VERSION 5.8 ;
BUSBITCHARS "[]" ;
DIVIDERCHAR "/" ;

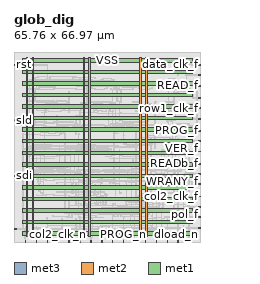
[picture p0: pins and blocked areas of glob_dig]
MACRO glob_dig
  CLASS BLOCK ;
  FOREIGN glob_dig 0 0 ;
  ORIGIN 0 0 ;
  SIZE 65.760 BY 66.970 ;
  SYMMETRY X Y ;
  PIN PROG_f
    DIRECTION OUTPUT ;
    USE SIGNAL ;
    PORT
      LAYER met3 ;
        RECT 64.960 39.075 65.760 39.375 ;
    END
  END PROG_f
  PIN PROG_n
    DIRECTION OUTPUT ;
    USE SIGNAL ;
    PORT
      LAYER met2 ;
        RECT 38.570 0.000 38.710 0.485 ;
    END
  END PROG_n
  PIN READ_f
    DIRECTION OUTPUT ;
    USE SIGNAL ;
    PORT
      LAYER met3 ;
        RECT 64.960 54.935 65.760 55.235 ;
    END
  END READ_f
  PIN READ_n
    DIRECTION OUTPUT ;
    USE SIGNAL ;
    PORT
      LAYER met2 ;
        RECT 53.930 0.000 54.070 0.485 ;
    END
  END READ_n
  PIN READb_f
    DIRECTION OUTPUT ;
    USE SIGNAL ;
    PORT
      LAYER met3 ;
        RECT 64.960 27.485 65.760 27.785 ;
    END
  END READb_f
  PIN READb_n
    DIRECTION OUTPUT ;
    USE SIGNAL ;
    PORT
      LAYER met2 ;
        RECT 27.050 0.000 27.190 0.485 ;
    END
  END READb_n
  PIN SENSE_f
    DIRECTION OUTPUT ;
    USE SIGNAL ;
    PORT
      LAYER met3 ;
        RECT 64.960 31.755 65.760 32.055 ;
    END
  END SENSE_f
  PIN SENSE_n
    DIRECTION OUTPUT ;
    USE SIGNAL ;
    PORT
      LAYER met2 ;
        RECT 30.890 0.000 31.030 0.485 ;
    END
  END SENSE_n
  PIN VDD
    DIRECTION INOUT ;
    USE POWER ;
    PORT
      LAYER met1 ;
        RECT 2.880 2.335 62.880 3.585 ;
        RECT 2.880 10.475 62.880 11.725 ;
        RECT 2.880 18.615 62.880 19.865 ;
        RECT 2.880 26.755 62.880 28.005 ;
        RECT 2.880 34.895 62.880 36.145 ;
        RECT 2.880 43.035 62.880 44.285 ;
        RECT 2.880 51.175 62.880 52.425 ;
        RECT 2.880 59.315 62.880 60.565 ;
      LAYER met2 ;
        RECT 4.380 2.060 4.880 64.910 ;
        RECT 24.380 2.060 24.880 64.910 ;
        RECT 44.380 2.060 44.880 64.910 ;
    END
  END VDD
  PIN VER_f
    DIRECTION OUTPUT ;
    USE SIGNAL ;
    PORT
      LAYER met3 ;
        RECT 64.960 35.415 65.760 35.715 ;
    END
  END VER_f
  PIN VER_n
    DIRECTION OUTPUT ;
    USE SIGNAL ;
    PORT
      LAYER met2 ;
        RECT 34.730 0.000 34.870 0.485 ;
    END
  END VER_n
  PIN VSS
    DIRECTION INOUT ;
    USE GROUND ;
    PORT
      LAYER met1 ;
        RECT 2.880 6.405 62.880 7.655 ;
        RECT 2.880 14.545 62.880 15.795 ;
        RECT 2.880 22.685 62.880 23.935 ;
        RECT 2.880 30.825 62.880 32.075 ;
        RECT 2.880 38.965 62.880 40.215 ;
        RECT 2.880 47.105 62.880 48.355 ;
        RECT 2.880 55.245 62.880 56.495 ;
        RECT 2.880 63.385 62.880 64.635 ;
      LAYER met2 ;
        RECT 6.380 2.060 6.880 64.910 ;
        RECT 26.380 2.060 26.880 64.910 ;
        RECT 46.380 2.060 46.880 64.910 ;
    END
  END VSS
  PIN WRANY_f
    DIRECTION OUTPUT ;
    USE SIGNAL ;
    PORT
      LAYER met3 ;
        RECT 64.960 23.825 65.760 24.125 ;
    END
  END WRANY_f
  PIN WRANY_n
    DIRECTION OUTPUT ;
    USE SIGNAL ;
    PORT
      LAYER met2 ;
        RECT 23.210 0.000 23.350 0.485 ;
    END
  END WRANY_n
  PIN col1_clk_f
    DIRECTION OUTPUT ;
    USE SIGNAL ;
    PORT
      LAYER met3 ;
        RECT 64.960 20.165 65.760 20.465 ;
    END
  END col1_clk_f
  PIN col1_clk_n
    DIRECTION OUTPUT ;
    USE SIGNAL ;
    PORT
      LAYER met2 ;
        RECT 19.370 0.000 19.510 0.485 ;
    END
  END col1_clk_n
  PIN col2_clk_f
    DIRECTION OUTPUT ;
    USE SIGNAL ;
    PORT
      LAYER met3 ;
        RECT 64.960 15.895 65.760 16.195 ;
    END
  END col2_clk_f
  PIN col2_clk_n
    DIRECTION OUTPUT ;
    USE SIGNAL ;
    PORT
      LAYER met2 ;
        RECT 15.530 0.000 15.670 0.485 ;
    END
  END col2_clk_n
  PIN data_clk_f
    DIRECTION OUTPUT ;
    USE SIGNAL ;
    PORT
      LAYER met3 ;
        RECT 64.960 62.255 65.760 62.555 ;
    END
  END data_clk_f
  PIN data_clk_n
    DIRECTION OUTPUT ;
    USE SIGNAL ;
    PORT
      LAYER met2 ;
        RECT 61.610 0.000 61.750 0.485 ;
    END
  END data_clk_n
  PIN dload_f
    DIRECTION OUTPUT ;
    USE SIGNAL ;
    PORT
      LAYER met3 ;
        RECT 64.960 58.595 65.760 58.895 ;
    END
  END dload_f
  PIN dload_n
    DIRECTION OUTPUT ;
    USE SIGNAL ;
    PORT
      LAYER met2 ;
        RECT 57.770 0.000 57.910 0.485 ;
    END
  END dload_n
  PIN pol_f
    DIRECTION OUTPUT ;
    USE SIGNAL ;
    PORT
      LAYER met3 ;
        RECT 64.960 12.235 65.760 12.535 ;
    END
  END pol_f
  PIN pol_n
    DIRECTION OUTPUT ;
    USE SIGNAL ;
    PORT
      LAYER met2 ;
        RECT 11.690 0.000 11.830 0.485 ;
    END
  END pol_n
  PIN rd_out_b_f
    DIRECTION OUTPUT ;
    USE SIGNAL ;
    PORT
      LAYER met3 ;
        RECT 64.960 4.915 65.760 5.215 ;
    END
  END rd_out_b_f
  PIN rd_out_b_n
    DIRECTION OUTPUT ;
    USE SIGNAL ;
    PORT
      LAYER met2 ;
        RECT 4.010 0.000 4.150 0.485 ;
    END
  END rd_out_b_n
  PIN rd_out_f
    DIRECTION OUTPUT ;
    USE SIGNAL ;
    PORT
      LAYER met3 ;
        RECT 64.960 8.575 65.760 8.875 ;
    END
  END rd_out_f
  PIN rd_out_n
    DIRECTION OUTPUT ;
    USE SIGNAL ;
    PORT
      LAYER met2 ;
        RECT 7.850 0.000 7.990 0.485 ;
    END
  END rd_out_n
  PIN row1_clk_f
    DIRECTION OUTPUT ;
    USE SIGNAL ;
    PORT
      LAYER met3 ;
        RECT 64.960 47.005 65.760 47.305 ;
    END
  END row1_clk_f
  PIN row1_clk_n
    DIRECTION OUTPUT ;
    USE SIGNAL ;
    PORT
      LAYER met2 ;
        RECT 46.250 0.000 46.390 0.485 ;
    END
  END row1_clk_n
  PIN row2_clk_f
    DIRECTION OUTPUT ;
    USE SIGNAL ;
    PORT
      LAYER met3 ;
        RECT 64.960 43.345 65.760 43.645 ;
    END
  END row2_clk_f
  PIN row2_clk_n
    DIRECTION OUTPUT ;
    USE SIGNAL ;
    PORT
      LAYER met2 ;
        RECT 42.410 0.000 42.550 0.485 ;
    END
  END row2_clk_n
  PIN rst
    DIRECTION INPUT ;
    USE SIGNAL ;
    PORT
      LAYER met3 ;
        RECT 0.000 62.255 0.800 62.555 ;
    END
  END rst
  PIN rstb_f
    DIRECTION OUTPUT ;
    USE SIGNAL ;
    PORT
      LAYER met3 ;
        RECT 64.960 50.665 65.760 50.965 ;
    END
  END rstb_f
  PIN rstb_n
    DIRECTION OUTPUT ;
    USE SIGNAL ;
    PORT
      LAYER met2 ;
        RECT 50.090 0.000 50.230 0.485 ;
    END
  END rstb_n
  PIN sck
    DIRECTION INPUT ;
    USE SIGNAL ;
    PORT
      LAYER met3 ;
        RECT 0.000 4.305 0.800 4.605 ;
    END
  END sck
  PIN sdi
    DIRECTION INPUT ;
    USE SIGNAL ;
    PORT
      LAYER met3 ;
        RECT 0.000 23.215 0.800 23.515 ;
    END
  END sdi
  PIN sld
    DIRECTION INPUT ;
    USE SIGNAL ;
    PORT
      LAYER met3 ;
        RECT 0.000 42.735 0.800 43.035 ;
    END
  END sld
  OBS
    LAYER li1 ;
      RECT 0.000 0.000 65.760 66.970 ;
    LAYER met1 ;
      RECT 30.335 4.510 30.625 4.555 ;
      RECT 30.335 4.695 30.625 4.740 ;
      RECT 11.210 4.555 36.650 4.695 ;
      RECT 36.650 4.325 36.790 4.695 ;
      RECT 6.815 4.880 7.105 4.925 ;
      RECT 40.970 4.185 41.110 4.555 ;
      RECT 36.650 4.185 40.970 4.325 ;
      RECT 41.930 4.555 42.070 4.925 ;
      RECT 40.970 4.555 41.930 4.695 ;
      RECT 7.105 4.925 11.210 5.065 ;
      RECT 6.815 4.925 7.105 5.110 ;
      RECT 11.210 4.695 11.350 5.065 ;
      RECT 41.930 4.925 61.055 5.065 ;
      RECT 61.055 4.880 61.345 5.110 ;
      RECT 29.375 5.435 29.665 5.480 ;
      RECT 11.690 5.110 11.830 5.665 ;
      RECT 11.615 4.880 11.905 5.110 ;
      RECT 11.690 5.665 22.250 5.805 ;
      RECT 22.250 5.435 22.390 5.805 ;
      RECT 30.410 5.295 30.550 5.805 ;
      RECT 31.370 5.665 31.510 5.850 ;
      RECT 30.550 5.665 31.370 5.805 ;
      RECT 22.250 5.295 30.410 5.435 ;
      RECT 29.375 5.250 29.665 5.295 ;
      RECT 33.770 5.665 48.560 5.805 ;
      RECT 48.560 5.605 48.880 5.865 ;
      RECT 31.370 5.850 33.770 5.990 ;
      RECT 33.770 5.805 33.910 5.990 ;
      RECT 18.335 8.765 18.625 8.810 ;
      RECT 24.170 9.735 24.310 9.920 ;
      RECT 21.290 9.735 24.170 9.875 ;
      RECT 24.170 9.920 29.930 10.060 ;
      RECT 29.930 9.875 30.070 10.060 ;
      RECT 17.840 10.045 18.160 10.105 ;
      RECT 20.330 8.625 20.470 10.105 ;
      RECT 18.335 8.580 18.625 8.765 ;
      RECT 18.625 8.625 20.330 8.765 ;
      RECT 44.330 9.735 44.470 10.105 ;
      RECT 29.930 9.735 44.330 9.875 ;
      RECT 18.160 10.105 21.290 10.245 ;
      RECT 17.840 10.105 18.160 10.305 ;
      RECT 21.290 9.875 21.430 10.245 ;
      RECT 44.330 10.105 45.200 10.245 ;
      RECT 45.200 10.045 45.520 10.305 ;
      RECT 30.815 12.095 31.105 12.140 ;
      RECT 31.850 11.955 31.990 12.140 ;
      RECT 30.815 11.910 31.105 12.095 ;
      RECT 31.105 11.955 31.850 12.095 ;
      RECT 35.690 11.955 37.520 12.095 ;
      RECT 37.520 11.895 37.840 12.155 ;
      RECT 31.850 12.140 35.690 12.280 ;
      RECT 35.690 12.095 35.830 12.280 ;
      RECT 19.280 12.635 19.600 12.835 ;
      RECT 36.170 12.695 36.310 12.880 ;
      RECT 19.600 12.695 36.170 12.835 ;
      RECT 19.280 12.835 19.600 12.895 ;
      RECT 36.170 12.880 38.570 13.020 ;
      RECT 38.570 12.835 38.710 13.020 ;
      RECT 51.530 13.065 61.055 13.205 ;
      RECT 61.055 13.020 61.345 13.250 ;
      RECT 40.010 12.695 40.150 13.205 ;
      RECT 38.570 12.695 40.010 12.835 ;
      RECT 49.130 13.065 49.270 13.435 ;
      RECT 40.150 13.065 49.130 13.205 ;
      RECT 49.130 13.435 51.530 13.575 ;
      RECT 51.530 13.205 51.670 13.575 ;
      RECT 33.695 20.790 33.985 20.835 ;
      RECT 33.985 20.835 34.730 20.975 ;
      RECT 33.695 20.835 33.985 21.020 ;
      RECT 34.730 20.605 34.870 20.975 ;
      RECT 37.130 20.465 37.270 21.205 ;
      RECT 34.730 20.465 37.130 20.605 ;
      RECT 39.440 21.145 39.760 21.205 ;
      RECT 42.890 21.020 43.030 21.205 ;
      RECT 40.490 21.020 42.890 21.160 ;
      RECT 42.890 21.205 49.535 21.345 ;
      RECT 49.535 21.160 49.825 21.390 ;
      RECT 39.440 21.345 39.760 21.405 ;
      RECT 37.130 21.205 40.490 21.345 ;
      RECT 40.490 21.160 40.630 21.345 ;
      RECT 7.775 21.900 8.065 21.945 ;
      RECT 10.160 21.885 10.480 21.945 ;
      RECT 14.090 21.575 14.230 21.945 ;
      RECT 11.210 21.575 14.090 21.715 ;
      RECT 17.855 21.900 18.145 21.945 ;
      RECT 31.850 21.205 31.990 21.945 ;
      RECT 24.650 21.205 31.850 21.345 ;
      RECT 34.655 21.900 34.945 21.945 ;
      RECT 7.775 22.085 8.065 22.130 ;
      RECT 17.855 22.085 18.145 22.130 ;
      RECT 14.090 21.945 24.650 22.085 ;
      RECT 24.650 21.345 24.790 22.085 ;
      RECT 34.655 22.085 34.945 22.130 ;
      RECT 10.160 22.085 10.480 22.145 ;
      RECT 7.775 21.945 11.210 22.085 ;
      RECT 11.210 21.715 11.350 22.085 ;
      RECT 31.850 21.945 35.600 22.085 ;
      RECT 35.600 21.885 35.920 22.145 ;
      RECT 31.775 24.490 32.065 24.535 ;
      RECT 32.065 24.535 38.570 24.675 ;
      RECT 31.775 24.535 32.065 24.720 ;
      RECT 38.570 24.490 38.710 24.675 ;
      RECT 44.735 24.860 45.025 25.090 ;
      RECT 44.810 24.535 44.950 24.860 ;
      RECT 41.930 24.350 42.070 24.675 ;
      RECT 42.070 24.535 44.810 24.675 ;
      RECT 38.570 24.350 41.930 24.490 ;
      RECT 25.040 24.845 25.360 24.905 ;
      RECT 55.295 25.045 55.585 25.090 ;
      RECT 25.360 24.905 26.090 25.045 ;
      RECT 25.040 24.905 25.360 25.105 ;
      RECT 26.090 24.675 26.230 25.045 ;
      RECT 30.410 24.535 30.550 24.905 ;
      RECT 26.090 24.535 30.410 24.675 ;
      RECT 31.370 24.905 31.510 25.275 ;
      RECT 30.410 24.905 31.370 25.045 ;
      RECT 40.490 24.905 40.630 25.275 ;
      RECT 39.050 24.905 40.490 25.045 ;
      RECT 49.610 24.905 49.750 25.275 ;
      RECT 48.650 24.905 49.610 25.045 ;
      RECT 31.370 25.275 39.050 25.415 ;
      RECT 39.050 25.045 39.190 25.415 ;
      RECT 49.610 25.275 53.450 25.415 ;
      RECT 53.450 25.045 53.590 25.415 ;
      RECT 40.895 25.415 41.185 25.460 ;
      RECT 61.130 25.275 62.015 25.415 ;
      RECT 62.015 25.230 62.305 25.460 ;
      RECT 41.930 25.275 42.070 25.645 ;
      RECT 40.895 25.230 41.185 25.275 ;
      RECT 40.490 25.275 41.930 25.415 ;
      RECT 58.730 24.905 58.870 25.645 ;
      RECT 53.450 24.905 58.730 25.045 ;
      RECT 55.295 24.860 55.585 24.905 ;
      RECT 45.290 25.275 48.650 25.415 ;
      RECT 48.650 25.045 48.790 25.415 ;
      RECT 41.930 25.645 45.290 25.785 ;
      RECT 45.290 25.415 45.430 25.785 ;
      RECT 58.730 25.645 61.130 25.785 ;
      RECT 61.130 25.415 61.270 25.785 ;
      RECT 33.695 29.300 33.985 29.345 ;
      RECT 36.095 29.300 36.385 29.345 ;
      RECT 33.695 29.485 33.985 29.530 ;
      RECT 36.095 29.485 36.385 29.530 ;
      RECT 33.695 29.345 41.375 29.485 ;
      RECT 41.375 29.300 41.665 29.530 ;
      RECT 32.255 30.040 32.545 30.085 ;
      RECT 32.255 30.225 32.545 30.270 ;
      RECT 32.255 30.085 34.160 30.225 ;
      RECT 34.160 30.025 34.480 30.285 ;
      RECT 3.455 32.630 3.745 32.675 ;
      RECT 5.360 32.615 5.680 32.675 ;
      RECT 3.455 32.815 3.745 32.860 ;
      RECT 18.815 32.815 19.105 32.860 ;
      RECT 5.360 32.815 5.680 32.875 ;
      RECT 33.290 32.675 34.160 32.815 ;
      RECT 34.160 32.615 34.480 32.875 ;
      RECT 22.730 32.675 22.870 33.000 ;
      RECT 28.970 32.860 29.110 33.045 ;
      RECT 22.870 32.860 28.970 33.000 ;
      RECT 3.455 32.675 22.730 32.815 ;
      RECT 18.815 32.630 19.105 32.675 ;
      RECT 28.970 33.045 33.290 33.185 ;
      RECT 33.290 32.815 33.430 33.185 ;
      RECT 15.920 33.725 16.240 33.785 ;
      RECT 35.120 33.725 35.440 33.785 ;
      RECT 5.855 33.925 6.145 33.970 ;
      RECT 21.215 33.925 21.505 33.970 ;
      RECT 28.490 33.785 36.575 33.925 ;
      RECT 36.575 33.740 36.865 33.970 ;
      RECT 15.920 33.925 16.240 33.985 ;
      RECT 35.120 33.925 35.440 33.985 ;
      RECT 6.890 33.785 7.030 34.155 ;
      RECT 5.855 33.740 6.145 33.925 ;
      RECT 6.145 33.785 6.890 33.925 ;
      RECT 22.250 33.785 22.390 34.155 ;
      RECT 13.130 33.785 22.250 33.925 ;
      RECT 21.215 33.740 21.505 33.785 ;
      RECT 6.890 34.155 13.130 34.295 ;
      RECT 13.130 33.925 13.270 34.295 ;
      RECT 22.250 34.155 28.490 34.295 ;
      RECT 28.490 33.925 28.630 34.295 ;
      RECT 33.695 45.950 33.985 45.995 ;
      RECT 33.695 46.135 33.985 46.180 ;
      RECT 33.695 45.995 34.640 46.135 ;
      RECT 34.640 45.935 34.960 46.195 ;
      RECT 23.120 45.565 23.440 45.625 ;
      RECT 23.120 45.765 23.440 45.825 ;
      RECT 46.175 45.950 46.465 45.995 ;
      RECT 46.250 45.255 46.390 45.950 ;
      RECT 29.450 45.255 46.250 45.395 ;
      RECT 29.375 45.950 29.665 46.180 ;
      RECT 29.450 45.395 29.590 45.950 ;
      RECT 23.120 45.625 29.450 45.765 ;
      RECT 46.175 46.135 46.465 46.180 ;
      RECT 46.175 45.995 47.120 46.135 ;
      RECT 47.120 45.935 47.440 46.195 ;
      RECT 34.655 48.910 34.945 48.955 ;
      RECT 34.655 49.095 34.945 49.140 ;
      RECT 23.600 49.095 23.920 49.155 ;
      RECT 33.770 48.955 35.600 49.095 ;
      RECT 35.600 48.895 35.920 49.155 ;
      RECT 26.570 48.955 26.710 49.325 ;
      RECT 23.600 48.895 23.920 49.095 ;
      RECT 23.920 48.955 26.570 49.095 ;
      RECT 26.570 49.325 33.770 49.465 ;
      RECT 33.770 49.095 33.910 49.465 ;
      RECT 22.160 54.815 22.480 54.875 ;
      RECT 34.250 54.690 34.390 54.875 ;
      RECT 23.210 54.690 34.250 54.830 ;
      RECT 36.080 54.815 36.400 54.875 ;
      RECT 42.890 54.505 43.030 54.875 ;
      RECT 38.090 54.505 42.890 54.645 ;
      RECT 42.890 54.875 47.135 55.015 ;
      RECT 47.135 54.830 47.425 55.060 ;
      RECT 22.480 54.875 23.210 55.015 ;
      RECT 23.210 54.830 23.350 55.015 ;
      RECT 22.160 54.875 22.480 55.075 ;
      RECT 36.080 55.015 36.400 55.075 ;
      RECT 34.250 54.875 38.090 55.015 ;
      RECT 38.090 54.645 38.230 55.015 ;
      RECT 25.520 56.665 25.840 56.725 ;
      RECT 25.520 56.725 33.695 56.865 ;
      RECT 33.695 56.680 33.985 56.910 ;
      RECT 25.520 56.865 25.840 56.925 ;
      RECT 30.335 57.235 30.625 57.280 ;
      RECT 34.250 57.095 35.120 57.235 ;
      RECT 35.120 57.035 35.440 57.295 ;
      RECT 31.370 57.095 31.510 57.465 ;
      RECT 30.335 57.050 30.625 57.235 ;
      RECT 30.625 57.095 31.370 57.235 ;
      RECT 31.370 57.465 34.250 57.605 ;
      RECT 34.250 57.235 34.390 57.605 ;
      RECT 54.320 37.795 54.640 37.855 ;
      RECT 54.320 37.855 56.735 37.995 ;
      RECT 56.735 37.810 57.025 38.040 ;
      RECT 54.320 37.995 54.640 38.055 ;
      RECT 35.600 38.165 35.920 38.225 ;
      RECT 35.600 38.225 36.575 38.365 ;
      RECT 36.575 38.180 36.865 38.410 ;
      RECT 35.600 38.365 35.920 38.425 ;
      RECT 49.055 38.180 49.345 38.225 ;
      RECT 49.055 38.365 49.345 38.410 ;
      RECT 49.055 38.225 53.840 38.365 ;
      RECT 53.840 38.165 54.160 38.425 ;
      RECT 35.120 40.385 35.440 40.645 ;
      RECT 35.615 40.400 35.905 40.445 ;
      RECT 35.615 40.585 35.905 40.630 ;
      RECT 35.615 40.445 38.480 40.585 ;
      RECT 38.480 40.385 38.800 40.645 ;
      RECT 60.095 40.770 60.385 40.815 ;
      RECT 60.095 40.955 60.385 41.000 ;
      RECT 60.095 40.815 64.400 40.955 ;
      RECT 64.400 40.755 64.720 41.015 ;
      RECT 34.640 41.125 34.960 41.185 ;
      RECT 41.930 40.815 42.070 41.185 ;
      RECT 39.530 40.815 41.930 40.955 ;
      RECT 42.800 41.125 43.120 41.185 ;
      RECT 41.930 41.185 52.895 41.325 ;
      RECT 52.895 41.140 53.185 41.370 ;
      RECT 34.960 41.185 35.830 41.325 ;
      RECT 34.640 41.185 34.960 41.385 ;
      RECT 35.830 41.000 39.530 41.140 ;
      RECT 35.690 41.000 35.830 41.185 ;
      RECT 39.530 40.955 39.670 41.140 ;
      RECT 42.800 41.325 43.120 41.385 ;
      RECT 34.175 41.510 34.465 41.555 ;
      RECT 36.575 41.510 36.865 41.555 ;
      RECT 34.175 41.695 34.465 41.740 ;
      RECT 36.575 41.695 36.865 41.740 ;
      RECT 34.175 41.555 41.855 41.695 ;
      RECT 41.855 41.510 42.145 41.740 ;
      RECT 57.200 41.495 57.520 41.555 ;
      RECT 57.200 41.555 61.535 41.695 ;
      RECT 61.535 41.510 61.825 41.740 ;
      RECT 57.200 41.695 57.520 41.755 ;
      RECT 37.040 42.605 37.360 42.665 ;
      RECT 46.250 42.295 46.390 42.665 ;
      RECT 38.090 42.295 46.250 42.435 ;
      RECT 46.250 42.665 47.135 42.805 ;
      RECT 47.135 42.620 47.425 42.850 ;
      RECT 37.360 42.665 38.090 42.805 ;
      RECT 37.040 42.665 37.360 42.865 ;
      RECT 38.090 42.435 38.230 42.805 ;
      RECT 53.855 42.620 54.145 42.665 ;
      RECT 53.855 42.805 54.145 42.850 ;
      RECT 53.855 42.665 55.280 42.805 ;
      RECT 55.280 42.605 55.600 42.865 ;
      RECT 37.040 45.565 37.360 45.625 ;
      RECT 37.040 45.625 37.535 45.765 ;
      RECT 37.535 45.580 37.825 45.810 ;
      RECT 37.040 45.765 37.360 45.825 ;
      RECT 62.015 45.580 62.305 45.625 ;
      RECT 62.015 45.765 62.305 45.810 ;
      RECT 62.015 45.625 62.960 45.765 ;
      RECT 62.960 45.565 63.280 45.825 ;
      RECT 42.815 45.950 43.105 45.995 ;
      RECT 42.815 46.135 43.105 46.180 ;
      RECT 42.815 45.995 44.255 46.135 ;
      RECT 44.255 45.950 44.545 46.180 ;
      RECT 35.615 33.370 35.905 33.415 ;
      RECT 38.015 33.370 38.305 33.415 ;
      RECT 35.615 33.555 35.905 33.600 ;
      RECT 38.015 33.555 38.305 33.600 ;
      RECT 35.615 33.415 43.295 33.555 ;
      RECT 43.295 33.370 43.585 33.600 ;
      RECT 38.480 34.465 38.800 34.525 ;
      RECT 47.690 34.155 47.830 34.525 ;
      RECT 39.530 34.155 47.690 34.295 ;
      RECT 47.690 34.525 48.575 34.665 ;
      RECT 48.575 34.480 48.865 34.710 ;
      RECT 38.800 34.525 39.530 34.665 ;
      RECT 38.480 34.525 38.800 34.725 ;
      RECT 39.530 34.295 39.670 34.665 ;
      RECT 48.080 45.935 48.400 46.195 ;
      RECT 53.375 45.950 53.665 45.995 ;
      RECT 53.375 46.135 53.665 46.180 ;
      RECT 53.375 45.995 54.320 46.135 ;
      RECT 54.320 45.935 54.640 46.195 ;
      RECT 55.280 45.935 55.600 45.995 ;
      RECT 55.280 45.995 55.775 46.135 ;
      RECT 55.775 45.950 56.065 46.180 ;
      RECT 55.280 46.135 55.600 46.195 ;
      RECT 49.130 45.995 51.935 46.135 ;
      RECT 51.935 45.950 52.225 46.180 ;
      RECT 45.695 46.320 45.985 46.365 ;
      RECT 45.985 46.365 49.130 46.505 ;
      RECT 45.695 46.365 45.985 46.550 ;
      RECT 49.130 46.135 49.270 46.505 ;
      RECT 35.600 46.305 35.920 46.565 ;
      RECT 49.520 46.675 49.840 46.935 ;
      RECT 46.655 48.540 46.945 48.585 ;
      RECT 46.655 48.725 46.945 48.770 ;
      RECT 46.655 48.585 48.080 48.725 ;
      RECT 48.080 48.525 48.400 48.785 ;
      RECT 61.535 48.540 61.825 48.585 ;
      RECT 61.535 48.725 61.825 48.770 ;
      RECT 61.535 48.585 62.960 48.725 ;
      RECT 62.960 48.525 63.280 48.785 ;
      RECT 57.680 36.315 58.000 36.575 ;
      RECT 41.855 49.280 42.145 49.325 ;
      RECT 41.855 49.465 42.145 49.510 ;
      RECT 41.855 49.325 44.735 49.465 ;
      RECT 44.735 49.280 45.025 49.510 ;
      RECT 53.375 49.280 53.665 49.325 ;
      RECT 53.375 49.465 53.665 49.510 ;
      RECT 53.375 49.325 55.775 49.465 ;
      RECT 55.775 49.280 56.065 49.510 ;
      RECT 46.655 49.280 46.945 49.325 ;
      RECT 46.655 49.465 46.945 49.510 ;
      RECT 46.655 49.325 47.120 49.465 ;
      RECT 47.120 49.265 47.440 49.525 ;
      RECT 49.520 49.265 49.840 49.325 ;
      RECT 49.520 49.325 50.015 49.465 ;
      RECT 50.015 49.280 50.305 49.510 ;
      RECT 49.520 49.465 49.840 49.525 ;
      RECT 36.080 49.635 36.400 49.695 ;
      RECT 36.080 49.695 36.575 49.835 ;
      RECT 36.575 49.650 36.865 49.880 ;
      RECT 36.080 49.835 36.400 49.895 ;
      RECT 56.735 52.795 57.025 52.840 ;
      RECT 62.090 52.655 62.960 52.795 ;
      RECT 62.960 52.595 63.280 52.855 ;
      RECT 57.770 52.655 57.910 53.025 ;
      RECT 56.735 52.610 57.025 52.795 ;
      RECT 57.025 52.655 57.770 52.795 ;
      RECT 57.770 53.025 62.090 53.165 ;
      RECT 62.090 52.795 62.230 53.165 ;
      RECT 34.175 53.720 34.465 53.765 ;
      RECT 36.575 53.720 36.865 53.765 ;
      RECT 34.175 53.905 34.465 53.950 ;
      RECT 36.575 53.905 36.865 53.950 ;
      RECT 34.175 53.765 41.855 53.905 ;
      RECT 41.855 53.720 42.145 53.950 ;
      RECT 56.240 53.705 56.560 53.765 ;
      RECT 56.240 53.765 62.015 53.905 ;
      RECT 62.015 53.720 62.305 53.950 ;
      RECT 56.240 53.905 56.560 53.965 ;
      RECT 35.615 54.090 35.905 54.135 ;
      RECT 35.615 54.275 35.905 54.320 ;
      RECT 35.615 54.135 37.040 54.275 ;
      RECT 37.040 54.075 37.360 54.335 ;
      RECT 47.690 53.765 47.830 54.135 ;
      RECT 44.810 53.765 47.690 53.905 ;
      RECT 47.690 54.135 48.575 54.275 ;
      RECT 48.575 54.090 48.865 54.320 ;
      RECT 43.990 54.135 44.810 54.275 ;
      RECT 44.810 53.905 44.950 54.275 ;
      RECT 43.775 54.460 44.065 54.690 ;
      RECT 43.850 54.135 43.990 54.460 ;
      RECT 35.120 54.445 35.440 54.705 ;
      RECT 60.560 54.445 60.880 54.705 ;
      RECT 43.775 36.515 44.065 36.560 ;
      RECT 54.890 36.375 55.760 36.515 ;
      RECT 55.760 36.315 56.080 36.575 ;
      RECT 44.810 36.375 44.950 36.745 ;
      RECT 43.775 36.330 44.065 36.515 ;
      RECT 44.065 36.375 44.810 36.515 ;
      RECT 44.810 36.745 54.890 36.885 ;
      RECT 54.890 36.515 55.030 36.885 ;
      RECT 38.480 37.425 38.800 37.685 ;
      RECT 47.120 37.425 47.440 37.485 ;
      RECT 47.120 37.485 50.495 37.625 ;
      RECT 50.495 37.440 50.785 37.670 ;
      RECT 47.120 37.625 47.440 37.685 ;
      RECT 54.410 57.295 54.550 57.465 ;
      RECT 54.320 57.035 54.640 57.295 ;
      RECT 54.410 57.465 56.735 57.605 ;
      RECT 56.735 57.420 57.025 57.650 ;
      RECT 57.680 58.885 58.000 59.145 ;
      RECT 57.680 62.215 58.000 62.475 ;
      RECT 61.535 62.600 61.825 62.645 ;
      RECT 61.535 62.785 61.825 62.830 ;
      RECT 61.535 62.645 62.480 62.785 ;
      RECT 62.480 62.585 62.800 62.845 ;
      RECT 20.735 40.955 21.025 41.000 ;
      RECT 31.850 40.815 32.735 40.955 ;
      RECT 32.735 40.770 33.025 41.000 ;
      RECT 24.170 40.815 24.310 41.185 ;
      RECT 20.735 40.770 21.025 40.955 ;
      RECT 21.025 40.815 24.170 40.955 ;
      RECT 24.170 41.185 31.850 41.325 ;
      RECT 31.850 40.955 31.990 41.325 ;
      RECT 7.775 46.320 8.065 46.365 ;
      RECT 10.640 46.305 10.960 46.365 ;
      RECT 16.490 45.995 16.630 46.365 ;
      RECT 12.170 45.995 16.490 46.135 ;
      RECT 17.375 46.320 17.665 46.365 ;
      RECT 7.775 46.505 8.065 46.550 ;
      RECT 17.375 46.505 17.665 46.550 ;
      RECT 10.640 46.505 10.960 46.565 ;
      RECT 7.775 46.365 12.170 46.505 ;
      RECT 12.170 46.135 12.310 46.505 ;
      RECT 16.490 46.365 23.600 46.505 ;
      RECT 23.600 46.305 23.920 46.565 ;
      RECT 12.170 40.445 12.310 40.630 ;
      RECT 10.250 40.445 12.170 40.585 ;
      RECT 15.530 40.445 18.815 40.585 ;
      RECT 18.815 40.400 19.105 40.630 ;
      RECT 12.170 40.630 15.530 40.770 ;
      RECT 15.530 40.585 15.670 40.770 ;
      RECT 7.280 41.125 7.600 41.185 ;
      RECT 7.280 41.185 10.175 41.325 ;
      RECT 10.175 41.140 10.465 41.370 ;
      RECT 10.250 40.585 10.390 41.140 ;
      RECT 7.280 41.325 7.600 41.385 ;
      RECT 14.960 41.125 15.280 41.385 ;
      RECT 27.920 48.525 28.240 48.585 ;
      RECT 27.920 48.585 30.815 48.725 ;
      RECT 30.815 48.540 31.105 48.770 ;
      RECT 27.920 48.725 28.240 48.785 ;
      RECT 21.680 41.125 22.000 41.385 ;
      RECT 20.255 33.370 20.545 33.415 ;
      RECT 22.655 33.370 22.945 33.415 ;
      RECT 20.255 33.555 20.545 33.600 ;
      RECT 22.655 33.555 22.945 33.600 ;
      RECT 20.255 33.415 27.935 33.555 ;
      RECT 27.935 33.370 28.225 33.600 ;
      RECT 11.120 48.525 11.440 48.725 ;
      RECT 12.170 48.585 12.310 48.770 ;
      RECT 11.440 48.585 12.170 48.725 ;
      RECT 18.410 48.585 19.295 48.725 ;
      RECT 19.295 48.540 19.585 48.770 ;
      RECT 11.120 48.725 11.440 48.785 ;
      RECT 12.170 48.770 18.410 48.910 ;
      RECT 18.410 48.725 18.550 48.910 ;
      RECT 15.440 41.125 15.760 41.185 ;
      RECT 16.895 41.325 17.185 41.370 ;
      RECT 15.440 41.325 15.760 41.385 ;
      RECT 22.250 41.185 23.120 41.325 ;
      RECT 23.120 41.125 23.440 41.385 ;
      RECT 21.290 41.185 21.430 41.555 ;
      RECT 15.440 41.185 21.290 41.325 ;
      RECT 16.895 41.140 17.185 41.185 ;
      RECT 21.290 41.555 22.250 41.695 ;
      RECT 22.250 41.325 22.390 41.695 ;
      RECT 2.960 37.795 3.280 37.855 ;
      RECT 8.255 37.810 8.545 37.855 ;
      RECT 8.255 37.995 8.545 38.040 ;
      RECT 2.960 37.855 9.290 37.995 ;
      RECT 9.290 37.625 9.430 37.995 ;
      RECT 2.960 37.995 3.280 38.055 ;
      RECT 16.010 37.485 16.150 38.225 ;
      RECT 9.290 37.485 16.010 37.625 ;
      RECT 16.010 38.225 17.360 38.365 ;
      RECT 17.360 38.165 17.680 38.425 ;
      RECT 4.895 33.370 5.185 33.415 ;
      RECT 7.295 33.370 7.585 33.415 ;
      RECT 4.895 33.555 5.185 33.600 ;
      RECT 7.295 33.555 7.585 33.600 ;
      RECT 4.895 33.415 12.575 33.555 ;
      RECT 12.575 33.370 12.865 33.600 ;
      RECT 5.360 42.235 5.680 42.295 ;
      RECT 14.090 41.925 14.230 42.295 ;
      RECT 11.210 41.925 14.090 42.065 ;
      RECT 14.090 42.295 20.735 42.435 ;
      RECT 20.735 42.250 21.025 42.480 ;
      RECT 5.680 42.295 11.210 42.435 ;
      RECT 5.360 42.295 5.680 42.495 ;
      RECT 11.210 42.065 11.350 42.435 ;
      RECT 16.400 37.795 16.720 38.055 ;
      RECT 7.775 49.465 8.065 49.510 ;
      RECT 18.410 49.325 19.280 49.465 ;
      RECT 19.280 49.265 19.600 49.525 ;
      RECT 15.050 49.325 15.190 49.695 ;
      RECT 7.775 49.280 8.065 49.465 ;
      RECT 8.065 49.325 15.050 49.465 ;
      RECT 15.050 49.695 18.410 49.835 ;
      RECT 18.410 49.465 18.550 49.835 ;
      RECT 6.335 49.650 6.625 49.695 ;
      RECT 8.735 49.650 9.025 49.695 ;
      RECT 6.335 49.835 6.625 49.880 ;
      RECT 8.735 49.835 9.025 49.880 ;
      RECT 6.335 49.695 14.015 49.835 ;
      RECT 14.015 49.650 14.305 49.880 ;
      RECT 4.895 49.650 5.185 49.695 ;
      RECT 4.895 49.835 5.185 49.880 ;
      RECT 4.895 49.695 5.360 49.835 ;
      RECT 5.360 49.635 5.680 49.895 ;
      RECT 25.520 49.635 25.840 49.895 ;
      RECT 9.215 38.550 9.505 38.595 ;
      RECT 9.215 38.735 9.505 38.780 ;
      RECT 9.215 38.595 10.640 38.735 ;
      RECT 10.640 38.535 10.960 38.795 ;
      RECT 7.280 50.005 7.600 50.265 ;
      RECT 19.280 52.595 19.600 52.855 ;
      RECT 14.960 44.455 15.280 44.715 ;
      RECT 7.280 53.335 7.600 53.595 ;
      RECT 6.335 53.720 6.625 53.765 ;
      RECT 8.735 53.720 9.025 53.765 ;
      RECT 6.335 53.905 6.625 53.950 ;
      RECT 8.735 53.905 9.025 53.950 ;
      RECT 6.335 53.765 14.015 53.905 ;
      RECT 14.015 53.720 14.305 53.950 ;
      RECT 21.680 44.455 22.000 44.515 ;
      RECT 21.680 44.515 24.575 44.655 ;
      RECT 24.575 44.470 24.865 44.700 ;
      RECT 21.680 44.655 22.000 44.715 ;
      RECT 4.895 53.720 5.185 53.765 ;
      RECT 4.895 53.905 5.185 53.950 ;
      RECT 4.895 53.765 5.360 53.905 ;
      RECT 5.360 53.705 5.680 53.965 ;
      RECT 9.695 45.580 9.985 45.625 ;
      RECT 9.695 45.765 9.985 45.810 ;
      RECT 9.695 45.625 11.120 45.765 ;
      RECT 11.120 45.565 11.440 45.825 ;
      RECT 27.440 54.075 27.760 54.135 ;
      RECT 31.850 53.765 31.990 54.135 ;
      RECT 28.490 53.765 31.850 53.905 ;
      RECT 31.850 54.135 32.735 54.275 ;
      RECT 32.735 54.090 33.025 54.320 ;
      RECT 27.760 54.135 28.490 54.275 ;
      RECT 27.440 54.135 27.760 54.335 ;
      RECT 28.490 53.905 28.630 54.275 ;
      RECT 19.280 45.565 19.600 45.825 ;
      RECT 24.650 53.765 24.790 54.135 ;
      RECT 21.770 53.765 24.650 53.905 ;
      RECT 7.775 54.275 8.065 54.320 ;
      RECT 24.650 54.135 25.520 54.275 ;
      RECT 25.520 54.075 25.840 54.335 ;
      RECT 8.810 54.135 8.950 54.505 ;
      RECT 7.775 54.090 8.065 54.275 ;
      RECT 8.065 54.135 8.810 54.275 ;
      RECT 14.710 54.135 21.770 54.275 ;
      RECT 21.770 53.905 21.910 54.275 ;
      RECT 8.810 54.505 14.570 54.645 ;
      RECT 14.570 54.135 14.710 54.645 ;
      RECT 11.135 38.550 11.425 38.595 ;
      RECT 14.570 38.225 14.710 38.595 ;
      RECT 12.170 38.225 14.570 38.365 ;
      RECT 11.425 38.595 12.170 38.735 ;
      RECT 11.135 38.595 11.425 38.780 ;
      RECT 12.170 38.365 12.310 38.735 ;
      RECT 14.570 38.595 15.440 38.735 ;
      RECT 15.440 38.535 15.760 38.795 ;
      RECT 21.680 40.385 22.000 40.445 ;
      RECT 21.680 40.445 23.135 40.585 ;
      RECT 23.135 40.400 23.425 40.630 ;
      RECT 21.680 40.585 22.000 40.645 ;
      RECT 17.840 37.795 18.160 38.055 ;
      RECT 27.920 45.935 28.240 46.195 ;
      RECT 22.160 56.665 22.480 56.925 ;
      RECT 21.680 37.795 22.000 38.055 ;
      RECT 5.360 57.035 5.680 57.095 ;
      RECT 19.295 57.050 19.585 57.095 ;
      RECT 19.295 57.235 19.585 57.280 ;
      RECT 5.360 57.235 5.680 57.295 ;
      RECT 5.360 57.095 27.440 57.235 ;
      RECT 27.440 57.035 27.760 57.295 ;
      RECT 10.640 40.755 10.960 40.815 ;
      RECT 10.640 40.815 11.135 40.955 ;
      RECT 11.135 40.770 11.425 41.000 ;
      RECT 10.640 40.955 10.960 41.015 ;
      RECT 16.400 40.755 16.720 41.015 ;
      RECT 11.600 57.405 11.920 57.665 ;
      RECT 20.735 57.790 21.025 57.835 ;
      RECT 23.135 57.790 23.425 57.835 ;
      RECT 20.735 57.975 21.025 58.020 ;
      RECT 23.135 57.975 23.425 58.020 ;
      RECT 20.735 57.835 28.415 57.975 ;
      RECT 28.415 57.790 28.705 58.020 ;
      RECT 7.280 57.975 7.600 58.035 ;
      RECT 8.330 57.835 8.470 58.205 ;
      RECT 7.280 57.775 7.600 57.975 ;
      RECT 7.600 57.835 8.330 57.975 ;
      RECT 12.650 58.020 12.790 58.205 ;
      RECT 12.575 57.790 12.865 58.020 ;
      RECT 11.690 57.835 12.575 57.975 ;
      RECT 8.330 58.205 11.690 58.345 ;
      RECT 11.690 57.975 11.830 58.345 ;
      RECT 12.650 58.205 21.695 58.345 ;
      RECT 21.695 58.160 21.985 58.390 ;
      RECT 17.360 40.755 17.680 40.815 ;
      RECT 17.360 40.815 17.855 40.955 ;
      RECT 17.855 40.770 18.145 41.000 ;
      RECT 17.360 40.955 17.680 41.015 ;
      RECT 22.640 37.795 22.960 38.055 ;
      RECT 30.890 45.995 32.255 46.135 ;
      RECT 32.255 45.950 32.545 46.180 ;
      RECT 28.895 46.320 29.185 46.365 ;
      RECT 29.185 46.365 30.890 46.505 ;
      RECT 28.895 46.365 29.185 46.550 ;
      RECT 30.890 46.135 31.030 46.505 ;
      RECT 15.920 30.025 16.240 30.285 ;
      RECT 21.680 7.825 22.000 8.085 ;
      RECT 7.280 30.395 7.600 30.455 ;
      RECT 9.200 30.395 9.520 30.455 ;
      RECT 15.050 30.085 15.190 30.455 ;
      RECT 10.250 30.085 15.050 30.225 ;
      RECT 15.050 30.455 19.295 30.595 ;
      RECT 19.295 30.410 19.585 30.640 ;
      RECT 7.280 30.595 7.600 30.655 ;
      RECT 9.200 30.595 9.520 30.655 ;
      RECT 7.280 30.455 10.250 30.595 ;
      RECT 10.250 30.225 10.390 30.595 ;
      RECT 6.335 32.260 6.625 32.305 ;
      RECT 6.335 32.445 6.625 32.490 ;
      RECT 6.335 32.305 7.280 32.445 ;
      RECT 7.280 32.245 7.600 32.505 ;
      RECT 21.680 32.245 22.000 32.305 ;
      RECT 21.680 32.305 33.215 32.445 ;
      RECT 33.215 32.260 33.505 32.490 ;
      RECT 21.680 32.445 22.000 32.505 ;
      RECT 11.600 8.195 11.920 8.455 ;
      RECT 17.855 33.000 18.145 33.045 ;
      RECT 19.760 32.985 20.080 33.045 ;
      RECT 17.855 33.185 18.145 33.230 ;
      RECT 17.855 33.045 21.695 33.185 ;
      RECT 21.695 33.000 21.985 33.230 ;
      RECT 19.760 33.185 20.080 33.245 ;
      RECT 27.440 8.195 27.760 8.455 ;
      RECT 22.640 8.565 22.960 8.825 ;
      RECT 23.120 8.565 23.440 8.625 ;
      RECT 23.120 8.625 31.295 8.765 ;
      RECT 31.295 8.580 31.585 8.810 ;
      RECT 23.120 8.765 23.440 8.825 ;
      RECT 13.535 8.950 13.825 8.995 ;
      RECT 13.535 9.135 13.825 9.180 ;
      RECT 13.535 8.995 19.280 9.135 ;
      RECT 19.280 8.935 19.600 9.195 ;
      RECT 25.040 9.305 25.360 9.365 ;
      RECT 25.360 9.365 28.970 9.505 ;
      RECT 25.040 9.365 25.360 9.565 ;
      RECT 28.970 9.180 29.110 9.505 ;
      RECT 28.895 8.950 29.185 9.180 ;
      RECT 15.440 3.755 15.760 3.815 ;
      RECT 15.440 3.815 17.375 3.955 ;
      RECT 17.375 3.770 17.665 4.000 ;
      RECT 15.440 3.955 15.760 4.015 ;
      RECT 3.920 5.235 4.240 5.495 ;
      RECT 31.280 13.005 31.600 13.065 ;
      RECT 31.280 13.065 31.775 13.205 ;
      RECT 31.775 13.020 32.065 13.250 ;
      RECT 31.280 13.205 31.600 13.265 ;
      RECT 7.760 5.235 8.080 5.495 ;
      RECT 21.680 13.375 22.000 13.435 ;
      RECT 21.680 13.435 23.615 13.575 ;
      RECT 23.615 13.390 23.905 13.620 ;
      RECT 21.680 13.575 22.000 13.635 ;
      RECT 28.880 13.375 29.200 13.435 ;
      RECT 28.880 13.435 29.375 13.575 ;
      RECT 29.375 13.390 29.665 13.620 ;
      RECT 28.880 13.575 29.200 13.635 ;
      RECT 30.320 13.375 30.640 13.635 ;
      RECT 25.040 13.745 25.360 14.005 ;
      RECT 25.535 13.575 25.825 13.620 ;
      RECT 28.490 13.435 28.630 13.805 ;
      RECT 25.535 13.390 25.825 13.575 ;
      RECT 25.825 13.435 28.490 13.575 ;
      RECT 28.490 13.805 32.240 13.945 ;
      RECT 32.240 13.745 32.560 14.005 ;
      RECT 32.330 13.250 32.470 13.745 ;
      RECT 32.255 13.020 32.545 13.250 ;
      RECT 19.280 15.965 19.600 16.025 ;
      RECT 19.280 16.025 25.535 16.165 ;
      RECT 25.535 15.980 25.825 16.210 ;
      RECT 19.280 16.165 19.600 16.225 ;
      RECT 29.375 15.980 29.665 16.025 ;
      RECT 29.375 16.165 29.665 16.210 ;
      RECT 29.375 16.025 31.280 16.165 ;
      RECT 31.280 15.965 31.600 16.225 ;
      RECT 30.320 16.335 30.640 16.395 ;
      RECT 30.320 16.395 32.735 16.535 ;
      RECT 32.735 16.350 33.025 16.580 ;
      RECT 30.320 16.535 30.640 16.595 ;
      RECT 7.775 16.350 8.065 16.395 ;
      RECT 7.775 16.535 8.065 16.580 ;
      RECT 14.090 16.395 18.335 16.535 ;
      RECT 18.335 16.350 18.625 16.580 ;
      RECT 10.160 16.535 10.480 16.595 ;
      RECT 11.210 16.395 11.350 16.765 ;
      RECT 7.775 16.395 11.210 16.535 ;
      RECT 10.160 16.335 10.480 16.395 ;
      RECT 11.210 16.765 14.090 16.905 ;
      RECT 14.090 16.535 14.230 16.905 ;
      RECT 21.680 16.535 22.000 16.595 ;
      RECT 22.730 16.395 22.870 16.765 ;
      RECT 21.680 16.335 22.000 16.535 ;
      RECT 22.000 16.395 22.730 16.535 ;
      RECT 28.970 16.595 29.110 16.765 ;
      RECT 28.880 16.335 29.200 16.595 ;
      RECT 26.090 16.395 28.880 16.535 ;
      RECT 22.730 16.765 26.090 16.905 ;
      RECT 26.090 16.535 26.230 16.905 ;
      RECT 28.970 16.765 29.375 16.905 ;
      RECT 29.375 16.720 29.665 16.950 ;
      RECT 27.935 16.720 28.225 16.765 ;
      RECT 27.935 16.905 28.225 16.950 ;
      RECT 27.935 16.765 28.400 16.905 ;
      RECT 28.400 16.705 28.720 16.965 ;
      RECT 9.200 17.075 9.520 17.135 ;
      RECT 9.200 17.135 9.695 17.275 ;
      RECT 9.695 17.090 9.985 17.320 ;
      RECT 9.200 17.275 9.520 17.335 ;
      RECT 20.255 17.090 20.545 17.135 ;
      RECT 20.255 17.275 20.545 17.320 ;
      RECT 20.255 17.135 20.720 17.275 ;
      RECT 20.720 17.075 21.040 17.335 ;
      RECT 31.775 16.720 32.065 16.765 ;
      RECT 31.775 16.765 32.240 16.905 ;
      RECT 32.240 16.705 32.560 16.965 ;
      RECT 14.975 17.460 15.265 17.505 ;
      RECT 15.265 17.505 31.850 17.645 ;
      RECT 14.975 17.505 15.265 17.690 ;
      RECT 31.850 16.950 31.990 17.645 ;
      RECT 31.775 16.905 32.065 16.950 ;
      RECT 28.400 20.035 28.720 20.295 ;
      RECT 14.975 20.790 15.265 20.835 ;
      RECT 21.680 20.775 22.000 20.835 ;
      RECT 27.530 20.465 27.670 20.835 ;
      RECT 24.170 20.465 27.530 20.605 ;
      RECT 14.975 20.975 15.265 21.020 ;
      RECT 27.530 20.835 30.815 20.975 ;
      RECT 30.815 20.790 31.105 21.020 ;
      RECT 21.680 20.975 22.000 21.035 ;
      RECT 14.975 20.835 24.170 20.975 ;
      RECT 24.170 20.605 24.310 20.975 ;
      RECT 8.240 21.145 8.560 21.205 ;
      RECT 8.240 21.205 9.695 21.345 ;
      RECT 9.695 21.160 9.985 21.390 ;
      RECT 8.240 21.345 8.560 21.405 ;
      RECT 19.760 21.145 20.080 21.405 ;
      RECT 16.880 5.235 17.200 5.495 ;
      RECT 25.055 21.530 25.345 21.575 ;
      RECT 25.055 21.715 25.345 21.760 ;
      RECT 27.455 21.715 27.745 21.760 ;
      RECT 29.450 21.575 29.590 21.945 ;
      RECT 25.055 21.575 29.450 21.715 ;
      RECT 27.455 21.530 27.745 21.575 ;
      RECT 29.450 21.945 31.295 22.085 ;
      RECT 31.295 21.900 31.585 22.130 ;
      RECT 21.680 5.235 22.000 5.495 ;
      RECT 30.320 22.255 30.640 22.315 ;
      RECT 30.320 22.315 30.815 22.455 ;
      RECT 30.815 22.270 31.105 22.500 ;
      RECT 30.320 22.455 30.640 22.515 ;
      RECT 7.280 24.105 7.600 24.365 ;
      RECT 21.200 24.105 21.520 24.165 ;
      RECT 21.200 24.165 23.615 24.305 ;
      RECT 23.615 24.120 23.905 24.350 ;
      RECT 21.200 24.305 21.520 24.365 ;
      RECT 15.455 24.490 15.745 24.535 ;
      RECT 15.920 24.475 16.240 24.535 ;
      RECT 15.455 24.675 15.745 24.720 ;
      RECT 15.455 24.535 23.135 24.675 ;
      RECT 23.135 24.490 23.425 24.720 ;
      RECT 15.920 24.675 16.240 24.735 ;
      RECT 30.800 5.235 31.120 5.295 ;
      RECT 30.800 5.295 33.215 5.435 ;
      RECT 33.215 5.250 33.505 5.480 ;
      RECT 30.800 5.435 31.120 5.495 ;
      RECT 4.415 24.860 4.705 24.905 ;
      RECT 5.360 24.845 5.680 24.905 ;
      RECT 4.415 25.045 4.705 25.090 ;
      RECT 19.850 24.905 20.735 25.045 ;
      RECT 20.735 24.860 21.025 25.090 ;
      RECT 5.360 25.045 5.680 25.105 ;
      RECT 4.415 24.905 8.330 25.045 ;
      RECT 8.330 24.675 8.470 25.045 ;
      RECT 14.090 24.535 14.230 24.905 ;
      RECT 8.330 24.535 14.090 24.675 ;
      RECT 15.050 24.905 15.190 25.275 ;
      RECT 14.090 24.905 15.050 25.045 ;
      RECT 15.050 25.275 19.850 25.415 ;
      RECT 19.850 25.045 19.990 25.415 ;
      RECT 5.855 25.230 6.145 25.275 ;
      RECT 8.255 25.230 8.545 25.275 ;
      RECT 5.855 25.415 6.145 25.460 ;
      RECT 8.255 25.415 8.545 25.460 ;
      RECT 5.855 25.275 13.535 25.415 ;
      RECT 13.535 25.230 13.825 25.460 ;
      RECT 22.175 25.230 22.465 25.275 ;
      RECT 24.575 25.230 24.865 25.275 ;
      RECT 22.175 25.415 22.465 25.460 ;
      RECT 24.575 25.415 24.865 25.460 ;
      RECT 22.175 25.275 29.855 25.415 ;
      RECT 29.855 25.230 30.145 25.460 ;
      RECT 19.280 3.755 19.600 3.955 ;
      RECT 20.330 3.815 20.470 4.000 ;
      RECT 19.600 3.815 20.330 3.955 ;
      RECT 23.690 3.815 24.575 3.955 ;
      RECT 24.575 3.770 24.865 4.000 ;
      RECT 19.280 3.955 19.600 4.015 ;
      RECT 20.330 4.000 23.690 4.140 ;
      RECT 23.690 3.955 23.830 4.140 ;
      RECT 7.760 26.325 8.080 26.385 ;
      RECT 17.930 26.015 18.070 26.385 ;
      RECT 8.810 26.015 17.930 26.155 ;
      RECT 17.930 26.385 18.815 26.525 ;
      RECT 18.815 26.340 19.105 26.570 ;
      RECT 8.080 26.385 8.810 26.525 ;
      RECT 7.760 26.385 8.080 26.585 ;
      RECT 8.810 26.155 8.950 26.525 ;
      RECT 6.335 29.300 6.625 29.345 ;
      RECT 8.735 29.300 9.025 29.345 ;
      RECT 6.335 29.485 6.625 29.530 ;
      RECT 8.735 29.485 9.025 29.530 ;
      RECT 6.335 29.345 14.015 29.485 ;
      RECT 14.015 29.300 14.305 29.530 ;
      RECT 16.880 7.825 17.200 8.085 ;
      RECT 7.760 29.655 8.080 29.915 ;
      RECT 4.895 30.040 5.185 30.085 ;
      RECT 4.895 30.225 5.185 30.270 ;
      RECT 4.895 30.085 5.360 30.225 ;
      RECT 5.360 30.025 5.680 30.285 ;
      RECT 34.655 30.410 34.945 30.455 ;
      RECT 34.655 30.595 34.945 30.640 ;
      RECT 34.655 30.455 35.120 30.595 ;
      RECT 35.120 30.395 35.440 30.655 ;
      RECT 37.040 30.395 37.360 30.455 ;
      RECT 45.770 30.085 45.910 30.455 ;
      RECT 38.090 30.085 45.770 30.225 ;
      RECT 45.770 30.455 46.655 30.595 ;
      RECT 46.655 30.410 46.945 30.640 ;
      RECT 37.360 30.455 38.090 30.595 ;
      RECT 37.040 30.455 37.360 30.655 ;
      RECT 38.090 30.225 38.230 30.595 ;
      RECT 36.560 12.265 36.880 12.325 ;
      RECT 49.535 12.280 49.825 12.325 ;
      RECT 49.535 12.465 49.825 12.510 ;
      RECT 36.560 12.465 36.880 12.525 ;
      RECT 36.560 12.325 50.960 12.465 ;
      RECT 50.960 12.265 51.280 12.525 ;
      RECT 37.040 17.075 37.360 17.135 ;
      RECT 37.040 17.135 37.535 17.275 ;
      RECT 37.535 17.090 37.825 17.320 ;
      RECT 37.040 17.275 37.360 17.335 ;
      RECT 37.040 32.245 37.360 32.505 ;
      RECT 51.920 32.245 52.240 32.305 ;
      RECT 51.920 32.305 52.415 32.445 ;
      RECT 52.415 32.260 52.705 32.490 ;
      RECT 51.920 32.445 52.240 32.505 ;
      RECT 61.520 32.245 61.840 32.505 ;
      RECT 50.960 17.075 51.280 17.135 ;
      RECT 50.960 17.135 61.535 17.275 ;
      RECT 61.535 17.090 61.825 17.320 ;
      RECT 50.960 17.275 51.280 17.335 ;
      RECT 47.135 8.395 47.425 8.440 ;
      RECT 52.010 8.255 52.880 8.395 ;
      RECT 52.880 8.195 53.200 8.455 ;
      RECT 49.610 8.255 49.750 8.625 ;
      RECT 47.135 8.210 47.425 8.395 ;
      RECT 47.425 8.255 49.610 8.395 ;
      RECT 49.610 8.625 52.010 8.765 ;
      RECT 52.010 8.395 52.150 8.765 ;
      RECT 49.520 32.985 49.840 33.245 ;
      RECT 57.680 32.985 58.000 33.245 ;
      RECT 59.600 5.605 59.920 5.865 ;
      RECT 37.055 4.880 37.345 4.925 ;
      RECT 37.055 5.065 37.345 5.110 ;
      RECT 37.055 4.925 41.360 5.065 ;
      RECT 41.360 4.865 41.680 5.125 ;
      RECT 38.480 8.565 38.800 8.825 ;
      RECT 53.840 8.565 54.160 8.825 ;
      RECT 35.120 21.145 35.440 21.205 ;
      RECT 35.120 21.205 36.575 21.345 ;
      RECT 36.575 21.160 36.865 21.390 ;
      RECT 35.120 21.345 35.440 21.405 ;
      RECT 34.640 13.375 34.960 13.435 ;
      RECT 34.640 13.435 35.615 13.575 ;
      RECT 35.615 13.390 35.905 13.620 ;
      RECT 34.640 13.575 34.960 13.635 ;
      RECT 62.015 21.160 62.305 21.205 ;
      RECT 62.015 21.345 62.305 21.390 ;
      RECT 62.015 21.205 62.480 21.345 ;
      RECT 62.480 21.145 62.800 21.405 ;
      RECT 41.855 21.530 42.145 21.575 ;
      RECT 41.855 21.715 42.145 21.760 ;
      RECT 41.855 21.575 42.335 21.715 ;
      RECT 42.335 21.530 42.625 21.760 ;
      RECT 54.335 21.530 54.625 21.575 ;
      RECT 54.335 21.715 54.625 21.760 ;
      RECT 54.335 21.575 55.775 21.715 ;
      RECT 55.775 21.530 56.065 21.760 ;
      RECT 50.960 21.515 51.280 21.775 ;
      RECT 42.800 13.375 43.120 13.635 ;
      RECT 51.050 3.815 51.935 3.955 ;
      RECT 51.935 3.770 52.225 4.000 ;
      RECT 45.680 3.955 46.000 4.015 ;
      RECT 46.730 3.815 46.870 4.185 ;
      RECT 45.680 3.755 46.000 3.955 ;
      RECT 46.000 3.815 46.730 3.955 ;
      RECT 46.730 4.185 51.050 4.325 ;
      RECT 51.050 3.955 51.190 4.325 ;
      RECT 48.095 21.900 48.385 21.945 ;
      RECT 48.095 22.085 48.385 22.130 ;
      RECT 48.095 21.945 53.840 22.085 ;
      RECT 53.840 21.885 54.160 22.145 ;
      RECT 35.135 8.950 35.425 8.995 ;
      RECT 35.135 9.135 35.425 9.180 ;
      RECT 35.135 8.995 36.560 9.135 ;
      RECT 36.560 8.935 36.880 9.195 ;
      RECT 39.920 22.255 40.240 22.315 ;
      RECT 39.920 22.315 43.295 22.455 ;
      RECT 43.295 22.270 43.585 22.500 ;
      RECT 39.920 22.455 40.240 22.515 ;
      RECT 47.120 13.745 47.440 14.005 ;
      RECT 59.600 13.745 59.920 14.005 ;
      RECT 50.000 24.105 50.320 24.165 ;
      RECT 50.000 24.165 52.895 24.305 ;
      RECT 52.895 24.120 53.185 24.350 ;
      RECT 50.000 24.305 50.320 24.365 ;
      RECT 56.255 24.120 56.545 24.165 ;
      RECT 56.255 24.305 56.545 24.350 ;
      RECT 56.255 24.165 56.720 24.305 ;
      RECT 56.720 24.105 57.040 24.365 ;
      RECT 47.690 13.805 48.095 13.945 ;
      RECT 48.095 13.760 48.385 13.990 ;
      RECT 39.440 14.115 39.760 14.175 ;
      RECT 39.530 13.250 39.670 14.115 ;
      RECT 39.455 13.020 39.745 13.250 ;
      RECT 46.250 13.990 46.390 14.175 ;
      RECT 40.490 13.990 46.250 14.130 ;
      RECT 46.250 14.175 47.690 14.315 ;
      RECT 47.690 13.945 47.830 14.315 ;
      RECT 39.760 14.175 40.490 14.315 ;
      RECT 40.490 14.130 40.630 14.315 ;
      RECT 39.440 14.175 39.760 14.375 ;
      RECT 60.575 24.490 60.865 24.535 ;
      RECT 60.575 24.675 60.865 24.720 ;
      RECT 60.575 24.535 62.960 24.675 ;
      RECT 62.960 24.475 63.280 24.735 ;
      RECT 37.520 8.935 37.840 8.995 ;
      RECT 41.375 8.950 41.665 8.995 ;
      RECT 41.375 9.135 41.665 9.180 ;
      RECT 37.520 9.135 37.840 9.195 ;
      RECT 37.520 8.995 47.120 9.135 ;
      RECT 47.120 8.935 47.440 9.195 ;
      RECT 41.360 24.845 41.680 25.105 ;
      RECT 48.560 8.935 48.880 9.195 ;
      RECT 56.255 15.980 56.545 16.025 ;
      RECT 56.255 16.165 56.545 16.210 ;
      RECT 56.255 16.025 58.640 16.165 ;
      RECT 58.640 15.965 58.960 16.225 ;
      RECT 42.815 16.165 43.105 16.210 ;
      RECT 43.850 16.025 43.990 16.210 ;
      RECT 42.815 15.980 43.105 16.165 ;
      RECT 43.105 16.025 43.850 16.165 ;
      RECT 47.690 16.025 48.560 16.165 ;
      RECT 48.560 15.965 48.880 16.225 ;
      RECT 43.850 16.210 47.690 16.350 ;
      RECT 47.690 16.165 47.830 16.350 ;
      RECT 39.920 25.215 40.240 25.475 ;
      RECT 56.720 8.935 57.040 9.195 ;
      RECT 35.600 16.335 35.920 16.595 ;
      RECT 35.120 26.325 35.440 26.585 ;
      RECT 60.080 16.335 60.400 16.595 ;
      RECT 42.320 3.755 42.640 3.815 ;
      RECT 42.320 3.815 43.775 3.955 ;
      RECT 43.775 3.770 44.065 4.000 ;
      RECT 42.320 3.955 42.640 4.015 ;
      RECT 41.840 29.285 42.160 29.345 ;
      RECT 41.840 29.345 54.335 29.485 ;
      RECT 54.335 29.300 54.625 29.530 ;
      RECT 41.840 29.485 42.160 29.545 ;
      RECT 55.760 29.285 56.080 29.345 ;
      RECT 55.760 29.345 60.095 29.485 ;
      RECT 60.095 29.300 60.385 29.530 ;
      RECT 55.760 29.485 56.080 29.545 ;
      RECT 42.320 5.235 42.640 5.495 ;
      RECT 35.120 29.655 35.440 29.915 ;
      RECT 57.215 29.670 57.505 29.715 ;
      RECT 57.215 29.855 57.505 29.900 ;
      RECT 57.215 29.715 57.680 29.855 ;
      RECT 57.680 29.655 58.000 29.915 ;
      RECT 48.575 16.720 48.865 16.765 ;
      RECT 48.575 16.905 48.865 16.950 ;
      RECT 48.575 16.765 50.495 16.905 ;
      RECT 50.495 16.720 50.785 16.950 ;
      RECT 42.320 11.895 42.640 12.155 ;
      RECT 45.200 16.705 45.520 16.965 ;
      RECT 52.880 30.025 53.200 30.285 ;
      RECT 51.920 5.235 52.240 5.495 ;
    LAYER met2 ;
      RECT 52.900 31.720 53.180 32.090 ;
      RECT 52.970 30.315 53.110 31.720 ;
      RECT 52.910 29.995 53.170 30.315 ;
      RECT 7.310 32.215 7.570 32.535 ;
      RECT 7.370 30.685 7.510 32.215 ;
      RECT 7.310 30.365 7.570 30.685 ;
      RECT 21.710 32.215 21.970 32.535 ;
      RECT 21.770 31.565 21.910 32.215 ;
      RECT 21.290 24.395 21.430 31.565 ;
      RECT 21.230 24.075 21.490 24.395 ;
      RECT 21.290 23.565 21.430 24.075 ;
      RECT 21.290 31.565 21.770 31.705 ;
      RECT 20.330 17.875 20.810 18.015 ;
      RECT 20.330 18.015 20.470 20.605 ;
      RECT 20.810 17.365 20.950 18.015 ;
      RECT 20.810 20.605 20.950 23.425 ;
      RECT 20.470 20.465 20.950 20.605 ;
      RECT 20.810 23.425 21.430 23.565 ;
      RECT 20.750 17.045 21.010 17.365 ;
      RECT 37.070 32.215 37.330 32.535 ;
      RECT 37.130 30.685 37.270 32.215 ;
      RECT 37.070 30.365 37.330 30.685 ;
      RECT 37.130 17.365 37.270 30.365 ;
      RECT 37.070 17.045 37.330 17.365 ;
      RECT 52.010 5.525 52.150 11.955 ;
      RECT 51.950 5.205 52.210 5.525 ;
      RECT 52.010 17.505 52.630 17.645 ;
      RECT 52.490 12.095 52.630 17.505 ;
      RECT 52.010 11.955 52.630 12.095 ;
      RECT 52.010 17.645 52.150 32.215 ;
      RECT 51.950 32.215 52.210 32.535 ;
      RECT 61.550 32.215 61.810 32.535 ;
      RECT 61.610 0.625 61.750 32.215 ;
      RECT 34.190 32.585 34.450 32.905 ;
      RECT 34.250 30.315 34.390 32.585 ;
      RECT 34.190 29.995 34.450 30.315 ;
      RECT 19.790 32.955 20.050 33.275 ;
      RECT 19.850 21.435 19.990 32.955 ;
      RECT 19.790 21.115 20.050 21.435 ;
      RECT 15.950 33.695 16.210 34.015 ;
      RECT 16.010 30.315 16.150 33.695 ;
      RECT 15.950 29.995 16.210 30.315 ;
      RECT 16.010 24.765 16.150 29.995 ;
      RECT 15.950 24.445 16.210 24.765 ;
      RECT 53.930 22.175 54.070 29.715 ;
      RECT 53.870 21.855 54.130 22.175 ;
      RECT 54.070 32.305 54.550 32.445 ;
      RECT 54.410 29.855 54.550 32.305 ;
      RECT 53.930 29.715 54.550 29.855 ;
      RECT 53.930 32.305 54.070 35.380 ;
      RECT 53.860 35.380 54.140 35.750 ;
      RECT 47.210 13.065 47.690 13.205 ;
      RECT 47.210 13.205 47.350 13.715 ;
      RECT 47.150 13.715 47.410 14.035 ;
      RECT 47.210 14.035 47.350 16.905 ;
      RECT 47.350 36.745 48.310 36.885 ;
      RECT 48.170 16.905 48.310 36.745 ;
      RECT 47.350 16.765 48.310 16.905 ;
      RECT 47.210 36.745 47.350 37.395 ;
      RECT 47.150 37.395 47.410 37.715 ;
      RECT 47.690 9.875 47.830 13.205 ;
      RECT 47.210 9.225 47.350 9.735 ;
      RECT 47.150 8.905 47.410 9.225 ;
      RECT 47.210 9.735 47.830 9.875 ;
      RECT 2.990 37.765 3.250 38.085 ;
      RECT 3.050 4.640 3.190 37.765 ;
      RECT 2.980 4.270 3.260 4.640 ;
      RECT 17.870 37.765 18.130 38.085 ;
      RECT 17.930 10.335 18.070 37.765 ;
      RECT 17.870 10.015 18.130 10.335 ;
      RECT 22.670 37.765 22.930 38.085 ;
      RECT 22.730 21.720 22.870 37.765 ;
      RECT 22.660 21.350 22.940 21.720 ;
      RECT 22.730 8.855 22.870 21.350 ;
      RECT 22.670 8.535 22.930 8.855 ;
      RECT 42.830 41.095 43.090 41.415 ;
      RECT 42.890 13.665 43.030 41.095 ;
      RECT 42.830 13.345 43.090 13.665 ;
      RECT 56.330 9.735 56.810 9.875 ;
      RECT 56.330 9.875 56.470 23.565 ;
      RECT 56.810 28.745 56.950 37.115 ;
      RECT 56.330 24.905 56.810 25.045 ;
      RECT 56.330 25.045 56.470 28.605 ;
      RECT 56.330 28.605 56.950 28.745 ;
      RECT 56.810 24.395 56.950 25.045 ;
      RECT 56.750 24.075 57.010 24.395 ;
      RECT 56.810 23.565 56.950 24.075 ;
      RECT 56.470 23.425 56.950 23.565 ;
      RECT 56.810 9.225 56.950 9.875 ;
      RECT 56.750 8.905 57.010 9.225 ;
      RECT 57.230 41.465 57.490 41.785 ;
      RECT 57.290 37.255 57.430 41.465 ;
      RECT 56.810 37.115 57.430 37.255 ;
      RECT 10.670 46.275 10.930 46.595 ;
      RECT 10.730 41.045 10.870 46.275 ;
      RECT 10.670 40.725 10.930 41.045 ;
      RECT 10.730 38.825 10.870 40.725 ;
      RECT 10.670 38.505 10.930 38.825 ;
      RECT 10.730 22.825 10.870 38.505 ;
      RECT 10.250 22.175 10.390 22.685 ;
      RECT 10.190 21.855 10.450 22.175 ;
      RECT 10.250 16.625 10.390 21.855 ;
      RECT 10.190 16.305 10.450 16.625 ;
      RECT 10.250 22.685 10.870 22.825 ;
      RECT 56.270 53.675 56.530 53.995 ;
      RECT 55.850 36.605 55.990 42.665 ;
      RECT 55.790 36.285 56.050 36.605 ;
      RECT 55.850 35.775 55.990 36.285 ;
      RECT 55.370 33.045 55.850 33.185 ;
      RECT 55.370 33.185 55.510 35.635 ;
      RECT 55.370 35.635 55.990 35.775 ;
      RECT 55.850 29.575 55.990 33.185 ;
      RECT 55.790 29.255 56.050 29.575 ;
      RECT 56.330 46.365 56.950 46.505 ;
      RECT 56.810 42.805 56.950 46.365 ;
      RECT 55.850 42.665 56.950 42.805 ;
      RECT 56.330 46.505 56.470 53.675 ;
      RECT 5.390 57.005 5.650 57.325 ;
      RECT 5.450 53.995 5.590 57.005 ;
      RECT 5.390 53.675 5.650 53.995 ;
      RECT 5.450 49.925 5.590 53.675 ;
      RECT 5.390 49.605 5.650 49.925 ;
      RECT 5.450 42.525 5.590 49.605 ;
      RECT 5.390 42.205 5.650 42.525 ;
      RECT 5.450 32.905 5.590 42.205 ;
      RECT 5.390 32.585 5.650 32.905 ;
      RECT 5.450 30.315 5.590 32.585 ;
      RECT 5.390 29.995 5.650 30.315 ;
      RECT 5.450 25.135 5.590 29.995 ;
      RECT 5.390 24.815 5.650 25.135 ;
      RECT 33.770 40.445 35.150 40.585 ;
      RECT 35.150 40.355 35.410 40.675 ;
      RECT 35.210 34.015 35.350 40.355 ;
      RECT 35.150 33.695 35.410 34.015 ;
      RECT 35.210 30.685 35.350 33.695 ;
      RECT 35.150 30.365 35.410 30.685 ;
      RECT 33.770 46.365 33.910 49.465 ;
      RECT 33.290 41.185 33.770 41.325 ;
      RECT 33.290 41.325 33.430 46.365 ;
      RECT 33.290 46.365 33.770 46.505 ;
      RECT 33.770 40.585 33.910 41.325 ;
      RECT 35.150 57.005 35.410 57.325 ;
      RECT 35.210 54.735 35.350 57.005 ;
      RECT 35.150 54.415 35.410 54.735 ;
      RECT 35.210 53.765 35.350 54.415 ;
      RECT 34.730 49.465 34.870 53.765 ;
      RECT 34.730 53.765 35.210 53.905 ;
      RECT 33.910 49.325 34.870 49.465 ;
      RECT 34.670 45.905 34.930 46.225 ;
      RECT 34.730 41.415 34.870 45.905 ;
      RECT 34.670 41.095 34.930 41.415 ;
      RECT 55.310 45.905 55.570 46.225 ;
      RECT 55.370 42.895 55.510 45.905 ;
      RECT 55.310 42.575 55.570 42.895 ;
      RECT 38.510 40.355 38.770 40.675 ;
      RECT 38.570 37.715 38.710 40.355 ;
      RECT 38.510 37.395 38.770 37.715 ;
      RECT 38.570 34.755 38.710 37.395 ;
      RECT 38.510 34.435 38.770 34.755 ;
      RECT 48.110 48.495 48.370 48.815 ;
      RECT 48.170 46.225 48.310 48.495 ;
      RECT 48.110 45.905 48.370 46.225 ;
      RECT 62.990 48.495 63.250 48.815 ;
      RECT 63.050 47.340 63.190 48.495 ;
      RECT 62.980 46.970 63.260 47.340 ;
      RECT 35.690 38.455 35.830 39.105 ;
      RECT 35.630 38.135 35.890 38.455 ;
      RECT 35.830 41.925 36.310 42.065 ;
      RECT 36.170 39.105 36.310 41.925 ;
      RECT 35.830 38.965 36.310 39.105 ;
      RECT 35.690 41.925 35.830 46.275 ;
      RECT 35.630 46.275 35.890 46.595 ;
      RECT 35.690 46.595 35.830 48.865 ;
      RECT 35.630 48.865 35.890 49.185 ;
      RECT 47.150 49.235 47.410 49.555 ;
      RECT 47.210 46.225 47.350 49.235 ;
      RECT 47.150 45.905 47.410 46.225 ;
      RECT 49.550 49.235 49.810 49.555 ;
      RECT 49.610 46.965 49.750 49.235 ;
      RECT 49.550 46.645 49.810 46.965 ;
      RECT 49.610 33.275 49.750 46.645 ;
      RECT 49.550 32.955 49.810 33.275 ;
      RECT 62.990 52.565 63.250 52.885 ;
      RECT 63.050 51.000 63.190 52.565 ;
      RECT 62.980 50.630 63.260 51.000 ;
      RECT 57.710 36.285 57.970 36.605 ;
      RECT 57.770 33.275 57.910 36.285 ;
      RECT 57.710 32.955 57.970 33.275 ;
      RECT 37.130 45.855 37.270 49.325 ;
      RECT 37.070 45.535 37.330 45.855 ;
      RECT 37.130 42.895 37.270 45.535 ;
      RECT 37.070 42.575 37.330 42.895 ;
      RECT 37.270 53.395 37.750 53.535 ;
      RECT 37.610 49.465 37.750 53.395 ;
      RECT 37.130 49.325 37.750 49.465 ;
      RECT 37.130 53.395 37.270 54.045 ;
      RECT 37.070 54.045 37.330 54.365 ;
      RECT 36.110 54.785 36.370 55.105 ;
      RECT 36.170 49.925 36.310 54.785 ;
      RECT 36.110 49.605 36.370 49.925 ;
      RECT 64.420 54.900 64.700 55.270 ;
      RECT 64.490 41.045 64.630 54.900 ;
      RECT 64.430 40.725 64.690 41.045 ;
      RECT 53.860 39.040 54.140 39.410 ;
      RECT 53.930 38.455 54.070 39.040 ;
      RECT 53.870 38.135 54.130 38.455 ;
      RECT 62.990 45.535 63.250 45.855 ;
      RECT 63.050 43.680 63.190 45.535 ;
      RECT 62.980 43.310 63.260 43.680 ;
      RECT 54.350 57.005 54.610 57.325 ;
      RECT 54.410 46.225 54.550 57.005 ;
      RECT 54.350 45.905 54.610 46.225 ;
      RECT 54.410 45.395 54.550 45.905 ;
      RECT 53.930 42.295 54.410 42.435 ;
      RECT 53.930 42.435 54.070 45.255 ;
      RECT 53.930 45.255 54.550 45.395 ;
      RECT 54.410 38.085 54.550 42.435 ;
      RECT 54.350 37.765 54.610 38.085 ;
      RECT 60.580 58.560 60.860 58.930 ;
      RECT 60.650 54.735 60.790 58.560 ;
      RECT 60.590 54.415 60.850 54.735 ;
      RECT 57.710 62.185 57.970 62.505 ;
      RECT 57.770 59.175 57.910 62.185 ;
      RECT 57.710 58.855 57.970 59.175 ;
      RECT 62.510 62.590 62.770 62.875 ;
      RECT 62.500 62.220 62.780 62.590 ;
      RECT 19.310 52.565 19.570 52.885 ;
      RECT 19.370 49.555 19.510 52.565 ;
      RECT 19.310 49.235 19.570 49.555 ;
      RECT 19.370 45.855 19.510 49.235 ;
      RECT 19.310 45.535 19.570 45.855 ;
      RECT 15.470 41.095 15.730 41.415 ;
      RECT 15.530 38.825 15.670 41.095 ;
      RECT 15.470 38.505 15.730 38.825 ;
      RECT 21.710 40.355 21.970 40.675 ;
      RECT 21.770 38.085 21.910 40.355 ;
      RECT 21.710 37.765 21.970 38.085 ;
      RECT 16.430 40.725 16.690 41.045 ;
      RECT 16.490 38.085 16.630 40.725 ;
      RECT 16.430 37.765 16.690 38.085 ;
      RECT 11.150 48.495 11.410 48.815 ;
      RECT 11.210 45.855 11.350 48.495 ;
      RECT 11.150 45.535 11.410 45.855 ;
      RECT 27.950 48.495 28.210 48.815 ;
      RECT 28.010 46.225 28.150 48.495 ;
      RECT 27.950 45.905 28.210 46.225 ;
      RECT 22.190 56.635 22.450 56.955 ;
      RECT 22.250 55.105 22.390 56.635 ;
      RECT 22.190 54.785 22.450 55.105 ;
      RECT 25.550 56.635 25.810 56.955 ;
      RECT 25.610 54.365 25.750 56.635 ;
      RECT 25.550 54.045 25.810 54.365 ;
      RECT 25.610 49.925 25.750 54.045 ;
      RECT 25.550 49.605 25.810 49.925 ;
      RECT 7.300 42.700 7.580 43.070 ;
      RECT 7.370 41.415 7.510 42.700 ;
      RECT 7.310 41.095 7.570 41.415 ;
      RECT 27.470 57.005 27.730 57.325 ;
      RECT 27.530 54.365 27.670 57.005 ;
      RECT 27.470 54.045 27.730 54.365 ;
      RECT 14.990 44.425 15.250 44.745 ;
      RECT 15.050 41.415 15.190 44.425 ;
      RECT 14.990 41.095 15.250 41.415 ;
      RECT 23.630 48.865 23.890 49.185 ;
      RECT 23.690 46.595 23.830 48.865 ;
      RECT 23.630 46.275 23.890 46.595 ;
      RECT 7.370 53.625 7.510 54.275 ;
      RECT 7.310 53.305 7.570 53.625 ;
      RECT 7.370 50.295 7.510 53.305 ;
      RECT 7.310 49.975 7.570 50.295 ;
      RECT 7.370 57.095 7.990 57.235 ;
      RECT 7.370 57.235 7.510 57.745 ;
      RECT 7.850 54.275 7.990 57.095 ;
      RECT 7.510 54.135 7.990 54.275 ;
      RECT 7.310 57.745 7.570 58.065 ;
      RECT 21.710 44.425 21.970 44.745 ;
      RECT 21.770 41.415 21.910 44.425 ;
      RECT 21.710 41.095 21.970 41.415 ;
      RECT 23.150 45.535 23.410 45.855 ;
      RECT 23.210 41.415 23.350 45.535 ;
      RECT 23.150 41.095 23.410 41.415 ;
      RECT 11.620 62.220 11.900 62.590 ;
      RECT 11.690 57.695 11.830 62.220 ;
      RECT 11.630 57.375 11.890 57.695 ;
      RECT 17.390 40.725 17.650 41.045 ;
      RECT 17.450 38.455 17.590 40.725 ;
      RECT 17.390 38.135 17.650 38.455 ;
      RECT 28.430 20.005 28.690 20.325 ;
      RECT 28.490 16.995 28.630 20.005 ;
      RECT 28.430 16.675 28.690 16.995 ;
      RECT 21.710 20.745 21.970 21.065 ;
      RECT 21.770 16.625 21.910 20.745 ;
      RECT 21.710 16.305 21.970 16.625 ;
      RECT 21.770 13.665 21.910 16.305 ;
      RECT 21.710 13.345 21.970 13.665 ;
      RECT 30.350 22.225 30.610 22.545 ;
      RECT 30.410 16.625 30.550 22.225 ;
      RECT 30.350 16.305 30.610 16.625 ;
      RECT 30.410 13.665 30.550 16.305 ;
      RECT 30.350 13.345 30.610 13.665 ;
      RECT 7.310 24.075 7.570 24.395 ;
      RECT 7.370 23.550 7.510 24.075 ;
      RECT 7.300 23.180 7.580 23.550 ;
      RECT 25.130 9.595 25.270 10.245 ;
      RECT 25.070 9.275 25.330 9.595 ;
      RECT 25.270 13.065 25.750 13.205 ;
      RECT 25.610 10.245 25.750 13.065 ;
      RECT 25.270 10.105 25.750 10.245 ;
      RECT 25.130 13.065 25.270 13.715 ;
      RECT 25.070 13.715 25.330 14.035 ;
      RECT 25.130 14.035 25.270 14.685 ;
      RECT 25.270 24.165 25.750 24.305 ;
      RECT 25.610 14.685 25.750 24.165 ;
      RECT 25.270 14.545 25.750 14.685 ;
      RECT 25.130 24.165 25.270 24.815 ;
      RECT 25.070 24.815 25.330 25.135 ;
      RECT 7.850 24.165 8.330 24.305 ;
      RECT 7.850 24.305 7.990 26.295 ;
      RECT 7.790 26.295 8.050 26.615 ;
      RECT 8.330 21.435 8.470 24.305 ;
      RECT 7.850 26.615 7.990 29.625 ;
      RECT 7.790 29.625 8.050 29.945 ;
      RECT 8.270 21.115 8.530 21.435 ;
      RECT 9.230 30.365 9.490 30.685 ;
      RECT 9.290 20.605 9.430 30.365 ;
      RECT 8.810 17.875 9.290 18.015 ;
      RECT 8.810 18.015 8.950 20.465 ;
      RECT 8.810 20.465 9.430 20.605 ;
      RECT 9.290 17.365 9.430 18.015 ;
      RECT 9.230 17.045 9.490 17.365 ;
      RECT 15.470 3.725 15.730 4.045 ;
      RECT 15.530 0.625 15.670 3.725 ;
      RECT 19.310 3.725 19.570 4.045 ;
      RECT 19.370 0.625 19.510 3.725 ;
      RECT 3.950 5.205 4.210 5.525 ;
      RECT 4.010 4.555 4.150 5.205 ;
      RECT 3.770 1.225 4.010 1.365 ;
      RECT 3.770 1.365 3.910 4.555 ;
      RECT 3.770 4.555 4.010 4.695 ;
      RECT 4.010 0.625 4.150 1.365 ;
      RECT 7.850 4.555 8.470 4.695 ;
      RECT 7.850 4.695 7.990 5.205 ;
      RECT 8.330 1.735 8.470 4.555 ;
      RECT 7.850 0.625 7.990 1.595 ;
      RECT 7.850 1.595 8.470 1.735 ;
      RECT 7.790 5.205 8.050 5.525 ;
      RECT 30.830 5.205 31.090 5.525 ;
      RECT 30.890 0.625 31.030 5.205 ;
      RECT 16.910 7.795 17.170 8.115 ;
      RECT 16.970 5.525 17.110 7.795 ;
      RECT 16.910 5.205 17.170 5.525 ;
      RECT 21.710 7.795 21.970 8.115 ;
      RECT 21.770 5.525 21.910 7.795 ;
      RECT 21.710 5.205 21.970 5.525 ;
      RECT 11.630 8.165 11.890 8.485 ;
      RECT 11.690 0.625 11.830 8.165 ;
      RECT 27.470 8.165 27.730 8.485 ;
      RECT 27.530 1.735 27.670 8.165 ;
      RECT 27.050 0.625 27.190 1.595 ;
      RECT 27.050 1.595 27.670 1.735 ;
      RECT 23.150 8.535 23.410 8.855 ;
      RECT 23.210 4.555 23.350 8.535 ;
      RECT 22.730 1.595 23.210 1.735 ;
      RECT 22.730 1.735 22.870 4.555 ;
      RECT 22.730 4.555 23.210 4.695 ;
      RECT 23.210 0.625 23.350 1.735 ;
      RECT 19.310 15.935 19.570 16.255 ;
      RECT 19.370 12.925 19.510 15.935 ;
      RECT 19.310 12.605 19.570 12.925 ;
      RECT 19.370 9.225 19.510 12.605 ;
      RECT 19.310 8.905 19.570 9.225 ;
      RECT 31.310 15.935 31.570 16.255 ;
      RECT 31.370 13.295 31.510 15.935 ;
      RECT 31.310 12.975 31.570 13.295 ;
      RECT 28.910 16.305 29.170 16.625 ;
      RECT 28.970 13.665 29.110 16.305 ;
      RECT 28.910 13.345 29.170 13.665 ;
      RECT 32.270 16.675 32.530 16.995 ;
      RECT 32.330 14.035 32.470 16.675 ;
      RECT 32.270 13.715 32.530 14.035 ;
      RECT 42.350 3.725 42.610 4.045 ;
      RECT 42.410 0.625 42.550 3.725 ;
      RECT 38.510 8.535 38.770 8.855 ;
      RECT 38.570 0.625 38.710 8.535 ;
      RECT 45.230 16.675 45.490 16.995 ;
      RECT 45.290 10.335 45.430 16.675 ;
      RECT 45.230 10.015 45.490 10.335 ;
      RECT 50.990 17.045 51.250 17.365 ;
      RECT 51.050 12.555 51.190 17.045 ;
      RECT 50.990 12.235 51.250 12.555 ;
      RECT 53.870 8.535 54.130 8.855 ;
      RECT 53.930 0.625 54.070 8.535 ;
      RECT 52.900 8.165 53.180 8.910 ;
      RECT 39.470 21.115 39.730 21.435 ;
      RECT 39.530 14.405 39.670 21.115 ;
      RECT 39.470 14.085 39.730 14.405 ;
      RECT 62.510 21.115 62.770 21.435 ;
      RECT 62.570 20.500 62.710 21.115 ;
      RECT 62.500 20.130 62.780 20.500 ;
      RECT 50.990 21.720 51.250 21.805 ;
      RECT 50.980 21.350 51.260 21.720 ;
      RECT 35.630 21.855 35.890 22.175 ;
      RECT 35.690 16.625 35.830 21.855 ;
      RECT 35.630 16.305 35.890 16.625 ;
      RECT 37.550 11.865 37.810 12.185 ;
      RECT 37.610 9.225 37.750 11.865 ;
      RECT 37.550 8.905 37.810 9.225 ;
      RECT 60.100 23.790 60.380 24.160 ;
      RECT 60.170 16.625 60.310 23.790 ;
      RECT 60.110 16.305 60.370 16.625 ;
      RECT 42.350 11.865 42.610 12.185 ;
      RECT 42.410 5.525 42.550 11.865 ;
      RECT 42.350 5.205 42.610 5.525 ;
      RECT 50.030 24.075 50.290 24.395 ;
      RECT 50.090 0.625 50.230 24.075 ;
      RECT 36.590 12.235 36.850 12.555 ;
      RECT 36.650 9.225 36.790 12.235 ;
      RECT 36.590 8.905 36.850 9.225 ;
      RECT 39.950 25.185 40.210 25.505 ;
      RECT 40.010 22.545 40.150 25.185 ;
      RECT 39.950 22.225 40.210 22.545 ;
      RECT 62.980 27.450 63.260 27.820 ;
      RECT 63.050 24.765 63.190 27.450 ;
      RECT 62.990 24.445 63.250 24.765 ;
      RECT 41.450 25.135 41.590 27.865 ;
      RECT 41.390 24.815 41.650 25.135 ;
      RECT 41.450 12.465 41.590 24.815 ;
      RECT 40.970 5.665 41.450 5.805 ;
      RECT 40.970 5.805 41.110 12.325 ;
      RECT 40.970 12.325 41.590 12.465 ;
      RECT 41.450 5.155 41.590 5.805 ;
      RECT 41.390 4.835 41.650 5.155 ;
      RECT 41.870 29.255 42.130 29.575 ;
      RECT 41.930 28.005 42.070 29.255 ;
      RECT 41.450 27.865 42.070 28.005 ;
      RECT 34.670 13.345 34.930 13.665 ;
      RECT 34.730 0.625 34.870 13.345 ;
      RECT 35.150 29.625 35.410 29.945 ;
      RECT 35.210 26.615 35.350 29.625 ;
      RECT 35.150 26.295 35.410 26.615 ;
      RECT 35.210 21.435 35.350 26.295 ;
      RECT 35.150 21.115 35.410 21.435 ;
      RECT 57.710 29.625 57.970 29.945 ;
      RECT 57.770 0.625 57.910 29.625 ;
      RECT 59.630 13.715 59.890 14.035 ;
      RECT 59.690 12.570 59.830 13.715 ;
      RECT 59.620 12.200 59.900 12.570 ;
      RECT 59.630 5.575 59.890 5.895 ;
      RECT 59.690 5.250 59.830 5.575 ;
      RECT 59.620 4.880 59.900 5.250 ;
      RECT 45.770 1.595 46.250 1.735 ;
      RECT 45.770 1.735 45.910 3.725 ;
      RECT 46.250 0.625 46.390 1.735 ;
      RECT 45.710 3.725 45.970 4.045 ;
      RECT 48.590 15.935 48.850 16.255 ;
      RECT 48.650 9.225 48.790 15.935 ;
      RECT 48.590 8.905 48.850 9.225 ;
      RECT 48.650 5.895 48.790 8.905 ;
      RECT 48.590 5.575 48.850 5.895 ;
      RECT 58.670 16.230 58.930 16.255 ;
      RECT 58.660 15.860 58.940 16.230 ;
    LAYER met3 ;
      RECT 1.100 4.305 2.955 4.605 ;
      RECT 2.955 4.290 3.285 4.620 ;
      RECT 59.925 4.915 64.660 5.215 ;
      RECT 59.595 4.900 59.925 5.230 ;
      RECT 53.205 8.575 64.660 8.875 ;
      RECT 52.875 8.560 53.205 8.890 ;
      RECT 59.925 12.235 64.660 12.535 ;
      RECT 59.595 12.220 59.925 12.550 ;
      RECT 58.965 15.895 64.660 16.195 ;
      RECT 58.635 15.880 58.965 16.210 ;
      RECT 62.805 20.165 64.660 20.465 ;
      RECT 62.475 20.150 62.805 20.480 ;
      RECT 22.635 21.370 22.965 21.385 ;
      RECT 22.635 21.685 22.965 21.700 ;
      RECT 22.635 21.385 50.955 21.685 ;
      RECT 50.955 21.370 51.285 21.700 ;
      RECT 1.100 23.215 7.275 23.515 ;
      RECT 7.275 23.200 7.605 23.530 ;
      RECT 60.405 23.825 64.660 24.125 ;
      RECT 60.075 23.810 60.405 24.140 ;
      RECT 63.285 27.485 64.660 27.785 ;
      RECT 62.955 27.470 63.285 27.800 ;
      RECT 53.205 31.755 64.660 32.055 ;
      RECT 52.875 31.740 53.205 32.070 ;
      RECT 54.165 35.415 64.660 35.715 ;
      RECT 53.835 35.400 54.165 35.730 ;
      RECT 54.165 39.075 64.660 39.375 ;
      RECT 53.835 39.060 54.165 39.390 ;
      RECT 1.100 42.735 7.275 43.035 ;
      RECT 7.275 42.720 7.605 43.050 ;
      RECT 63.285 43.345 64.660 43.645 ;
      RECT 62.955 43.330 63.285 43.660 ;
      RECT 63.285 47.005 64.660 47.305 ;
      RECT 62.955 46.990 63.285 47.320 ;
      RECT 63.285 50.665 64.660 50.965 ;
      RECT 62.955 50.650 63.285 50.980 ;
      RECT 64.395 54.920 64.660 55.250 ;
      RECT 60.885 58.595 64.660 58.895 ;
      RECT 60.555 58.580 60.885 58.910 ;
      RECT 1.100 62.255 11.595 62.555 ;
      RECT 11.595 62.240 11.925 62.570 ;
      RECT 62.805 62.255 64.660 62.555 ;
      RECT 62.475 62.240 62.805 62.570 ;
  END
END glob_dig

END LIBRARY
